One B-rep face of a CAD part: STEP entity #1476.
In plain terms, the planar face has unit normal (1, 0, 0).
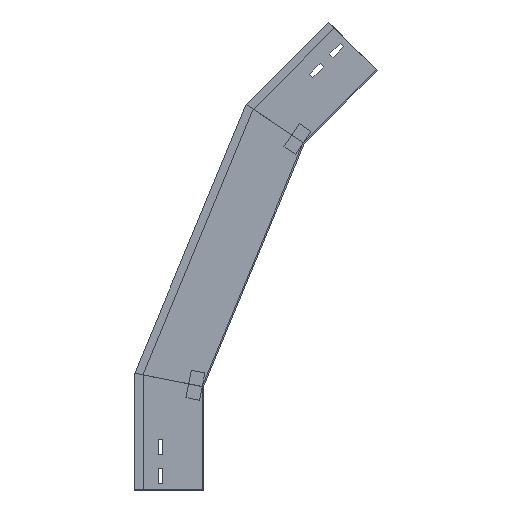
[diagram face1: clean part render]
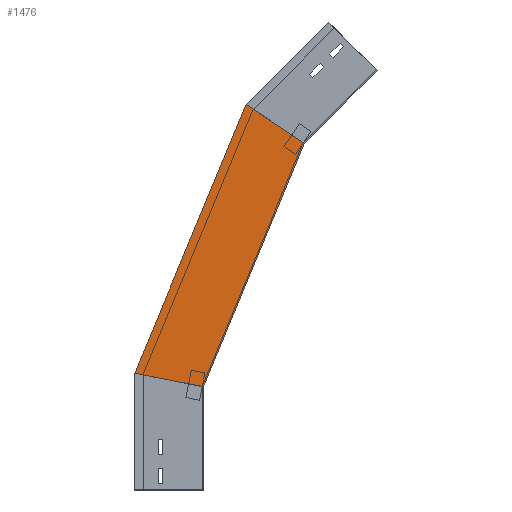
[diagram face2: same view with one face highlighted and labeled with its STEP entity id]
Its self-contained STEP definition (entity closure, numbers rounded to 3 decimals):
#67 = DIRECTION ( 'NONE',  ( 0., -0.383, 0.924 ) ) ;
#70 = VECTOR ( 'NONE', #1402, 1000. ) ;
#74 = VECTOR ( 'NONE', #1422, 1000. ) ;
#82 = EDGE_LOOP ( 'NONE', ( #114, #805, #943, #1219 ) ) ;
#114 = ORIENTED_EDGE ( 'NONE', *, *, #1453, .T. ) ;
#322 = DIRECTION ( 'NONE',  ( 1., 0., 0. ) ) ;
#447 = VERTEX_POINT ( 'NONE', #1414 ) ;
#450 = CARTESIAN_POINT ( 'NONE',  ( 0., -61.792, 560.491 ) ) ;
#454 = VECTOR ( 'NONE', #1008, 1000. ) ;
#463 = LINE ( 'NONE', #1392, #70 ) ;
#473 = EDGE_CURVE ( 'NONE', #853, #447, #1151, .T. ) ;
#523 = CARTESIAN_POINT ( 'NONE',  ( 0., 100., 169.891 ) ) ;
#541 = PLANE ( 'NONE',  #1225 ) ;
#660 = FACE_OUTER_BOUND ( 'NONE', #82, .T. ) ;
#668 = LINE ( 'NONE', #1347, #454 ) ;
#723 = VECTOR ( 'NONE', #67, 1000. ) ;
#752 = CARTESIAN_POINT ( 'NONE',  ( 0., 0., 150. ) ) ;
#777 = DIRECTION ( 'NONE',  ( 0., 0., -1. ) ) ;
#805 = ORIENTED_EDGE ( 'NONE', *, *, #473, .T. ) ;
#853 = VERTEX_POINT ( 'NONE', #450 ) ;
#943 = ORIENTED_EDGE ( 'NONE', *, *, #1415, .F. ) ;
#1008 = DIRECTION ( 'NONE',  ( 0., -0.383, 0.924 ) ) ;
#1094 = LINE ( 'NONE', #1243, #723 ) ;
#1114 = CARTESIAN_POINT ( 'NONE',  ( 0., 8.412, 129.693 ) ) ;
#1151 = LINE ( 'NONE', #1299, #74 ) ;
#1219 = ORIENTED_EDGE ( 'NONE', *, *, #1290, .F. ) ;
#1225 = AXIS2_PLACEMENT_3D ( 'NONE', #1114, #322, #777 ) ;
#1243 = CARTESIAN_POINT ( 'NONE',  ( 0., 100.799, 167.961 ) ) ;
#1290 = EDGE_CURVE ( 'NONE', #1478, #1420, #463, .T. ) ;
#1299 = CARTESIAN_POINT ( 'NONE',  ( 0., -212.26, 459.952 ) ) ;
#1347 = CARTESIAN_POINT ( 'NONE',  ( 0., 8.412, 129.693 ) ) ;
#1392 = CARTESIAN_POINT ( 'NONE',  ( 0., -28.701, 144.291 ) ) ;
#1402 = DIRECTION ( 'NONE',  ( 0., -0.981, -0.195 ) ) ;
#1414 = CARTESIAN_POINT ( 'NONE',  ( 0., -146.568, 503.846 ) ) ;
#1415 = EDGE_CURVE ( 'NONE', #1420, #447, #668, .T. ) ;
#1420 = VERTEX_POINT ( 'NONE', #752 ) ;
#1422 = DIRECTION ( 'NONE',  ( 0., -0.831, -0.556 ) ) ;
#1453 = EDGE_CURVE ( 'NONE', #1478, #853, #1094, .T. ) ;
#1476 = ADVANCED_FACE ( 'NONE', ( #660 ), #541, .T. ) ;
#1478 = VERTEX_POINT ( 'NONE', #523 ) ;
